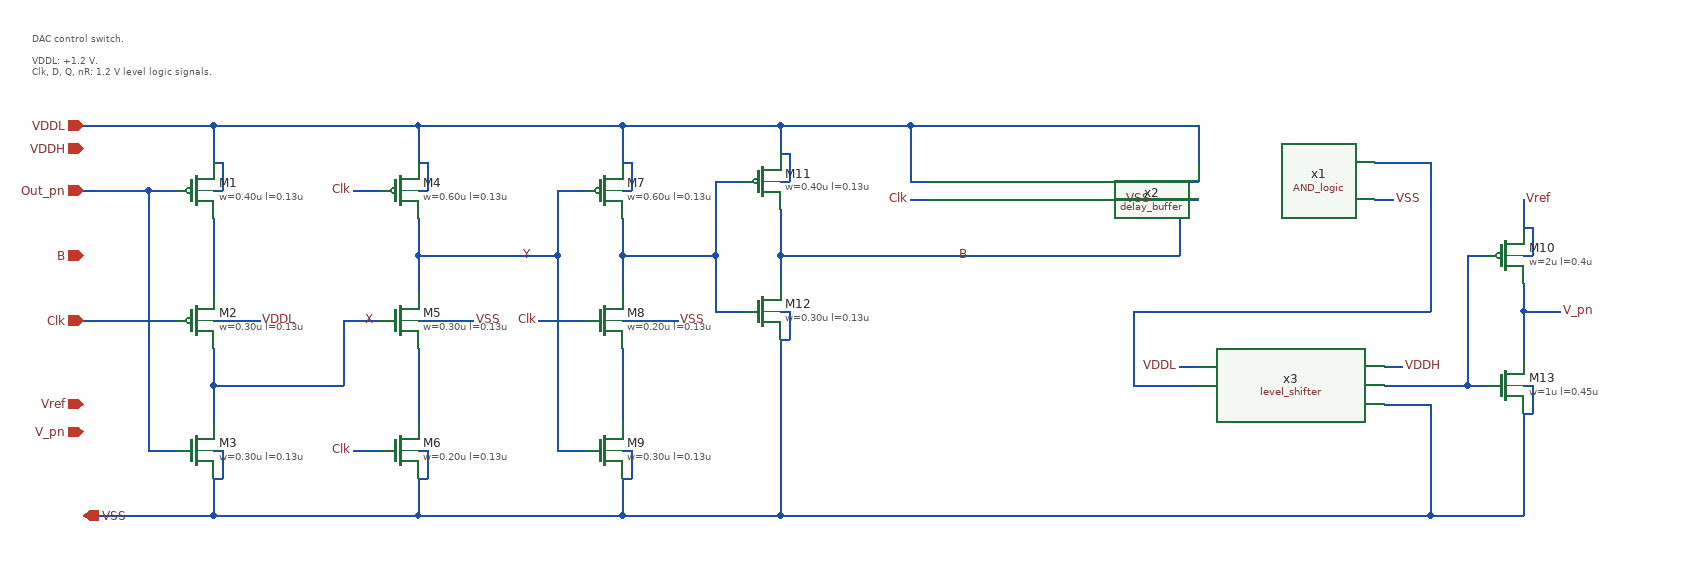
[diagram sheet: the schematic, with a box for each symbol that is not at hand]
v {xschem version=3.4.8RC file_version=1.3}
G {}
K {}
V {}
S {}
F {}
E {}
T {DAC control switch.

VDDL: +1.2 V.
Clk, D, Q, nR: 1.2 V level logic signals.} -245 -265 0 0 0.3 0.3 {}
N -50 -60 -50 20 {lab=#net1}
N -50 -160 -50 -120 {lab=VDDL}
N -50 120 -50 160 {lab=X}
N -50 220 -50 260 {lab=VSS}
N -50 -90 -40 -90 {lab=VDDL}
N -40 -120 -40 -90 {lab=VDDL}
N -50 -120 -40 -120 {lab=VDDL}
N -50 50 0 50 {lab=VDDL}
N -50 190 -40 190 {lab=VSS}
N -40 190 -40 220 {lab=VSS}
N -50 220 -40 220 {lab=VSS}
N -120 -90 -90 -90 {lab=Out_pn}
N -120 -90 -120 190 {lab=Out_pn}
N -120 190 -90 190 {lab=Out_pn}
N -190 -90 -120 -90 {lab=Out_pn}
N -190 50 -90 50 {lab=Clk}
N -190 -160 -50 -160 {lab=VDDL}
N -190 260 -50 260 {lab=VSS}
N 170 -90 180 -90 {lab=VDDL}
N 180 -120 180 -90 {lab=VDDL}
N 170 -120 180 -120 {lab=VDDL}
N 170 -160 170 -120 {lab=VDDL}
N -50 -160 170 -160 {lab=VDDL}
N 90 50 130 50 {lab=X}
N 90 50 90 120 {lab=X}
N -50 120 90 120 {lab=X}
N -50 80 -50 120 {lab=X}
N 100 -90 130 -90 {lab=Clk}
N 100 190 130 190 {lab=Clk}
N 170 80 170 160 {lab=#net2}
N 170 220 170 260 {lab=VSS}
N -50 260 170 260 {lab=VSS}
N 170 -20 170 20 {lab=Y}
N 170 50 230 50 {lab=VSS}
N 170 190 180 190 {lab=VSS}
N 180 190 180 220 {lab=VSS}
N 170 220 180 220 {lab=VSS}
N 390 -90 400 -90 {lab=VDDL}
N 400 -120 400 -90 {lab=VDDL}
N 390 -120 400 -120 {lab=VDDL}
N 390 -160 390 -120 {lab=VDDL}
N 390 80 390 160 {lab=#net3}
N 390 220 390 260 {lab=VSS}
N 390 -20 390 20 {lab=#net4}
N 390 50 450 50 {lab=VSS}
N 390 190 400 190 {lab=VSS}
N 400 190 400 220 {lab=VSS}
N 390 220 400 220 {lab=VSS}
N 320 -90 350 -90 {lab=Y}
N 320 -20 320 190 {lab=Y}
N 320 190 350 190 {lab=Y}
N 170 260 390 260 {lab=VSS}
N 170 -160 390 -160 {lab=VDDL}
N 170 -20 320 -20 {lab=Y}
N 170 -60 170 -20 {lab=Y}
N 320 -90 320 -20 {lab=Y}
N 390 -160 560 -160 {lab=VDDL}
N 300 50 350 50 {lab=Clk}
N 560 -100 570 -100 {lab=VDDL}
N 570 -130 570 -100 {lab=VDDL}
N 560 -130 570 -130 {lab=VDDL}
N 490 -100 520 -100 {lab=#net4}
N 560 -20 560 10 {lab=B}
N 560 40 570 40 {lab=VSS}
N 570 40 570 70 {lab=VSS}
N 560 70 570 70 {lab=VSS}
N 560 70 560 260 {lab=VSS}
N 390 260 560 260 {lab=VSS}
N 390 -60 390 -20 {lab=#net4}
N 490 -20 490 40 {lab=#net4}
N 490 -100 490 -20 {lab=#net4}
N 490 40 520 40 {lab=#net4}
N 390 -20 490 -20 {lab=#net4}
N 560 -160 560 -130 {lab=VDDL}
N 560 -70 560 -20 {lab=B}
N 910 -100 1010 -100 {lab=#net5}
N 910 -80 930 -80 {lab=VSS}
N 1200 -80 1220 -80 {lab=VSS}
N 1010 -160 1010 -120 {lab=VDDL}
N 700 -100 720 -100 {lab=VDDL}
N 700 -160 700 -100 {lab=VDDL}
N 700 -160 1010 -160 {lab=VDDL}
N 560 -160 700 -160 {lab=VDDL}
N 700 -80 720 -80 {lab=Clk}
N 560 -20 990 -20 {lab=B}
N 990 -80 990 -20 {lab=B}
N 990 -80 1010 -80 {lab=B}
N 1360 -20 1370 -20 {lab=Vref}
N 1370 -50 1370 -20 {lab=Vref}
N 1360 -50 1370 -50 {lab=Vref}
N 1300 -20 1320 -20 {lab=#net6}
N 1360 120 1370 120 {lab=VSS}
N 1370 120 1370 150 {lab=VSS}
N 1300 120 1320 120 {lab=#net6}
N 1360 40 1360 90 {lab=V_pn}
N 1360 -80 1360 -50 {lab=Vref}
N 1300 -20 1300 120 {lab=#net6}
N 1360 40 1400 40 {lab=V_pn}
N 1360 10 1360 40 {lab=V_pn}
N 1200 -120 1260 -120 {lab=#net7}
N 1260 -120 1260 40 {lab=#net7}
N 940 120 1010 120 {lab=#net7}
N 990 100 1010 100 {lab=VDDL}
N 940 40 1260 40 {lab=#net7}
N 940 40 940 120 {lab=#net7}
N 1360 150 1370 150 {lab=VSS}
N 1260 260 1360 260 {lab=VSS}
N 1360 150 1360 260 {lab=VSS}
N 1260 140 1260 260 {lab=VSS}
N 560 260 1260 260 {lab=VSS}
N 1210 100 1230 100 {lab=VDDH}
N 1210 120 1300 120 {lab=#net6}
N 1210 140 1260 140 {lab=VSS}
C {title.sym} -160 420 0 0 {name=l1 author="Ernestas Gruodis - Kaunas University of Technology"}
C {sg13g2_pr/sg13_lv_pmos.sym} -70 -90 0 0 {name=M1
l=0.13u
w=0.40u
ng=1
m=1
model=sg13_lv_pmos
spiceprefix=X
}
C {sg13g2_pr/sg13_lv_pmos.sym} -70 50 0 0 {name=M2
l=0.13u
w=0.30u
ng=1
m=1
model=sg13_lv_pmos
spiceprefix=X
}
C {sg13g2_pr/sg13_lv_nmos.sym} -70 190 0 0 {name=M3
l=0.13u
w=0.30u
ng=1
m=1
model=sg13_lv_nmos
spiceprefix=X
}
C {lab_wire.sym} 0 50 0 1 {name=p1 sig_type=std_logic lab=VDDL}
C {ipin.sym} -190 -90 0 0 {name=p2 lab=Out_pn}
C {ipin.sym} -190 50 0 0 {name=p3 lab=Clk}
C {ipin.sym} -190 -160 0 0 {name=p4 lab=VDDL}
C {sg13g2_pr/sg13_lv_pmos.sym} 150 -90 0 0 {name=M4
l=0.13u
w=0.60u
ng=1
m=1
model=sg13_lv_pmos
spiceprefix=X
}
C {sg13g2_pr/sg13_lv_nmos.sym} 150 50 0 0 {name=M5
l=0.13u
w=0.30u
ng=1
m=1
model=sg13_lv_nmos
spiceprefix=X
}
C {sg13g2_pr/sg13_lv_nmos.sym} 150 190 0 0 {name=M6
l=0.13u
w=0.20u
ng=1
m=1
model=sg13_lv_nmos
spiceprefix=X
}
C {lab_wire.sym} 110 50 0 1 {name=p6 sig_type=std_logic lab=X}
C {lab_wire.sym} 100 -90 0 0 {name=p7 sig_type=std_logic lab=Clk}
C {lab_wire.sym} 100 190 0 0 {name=p8 sig_type=std_logic lab=Clk}
C {lab_wire.sym} 230 50 0 1 {name=p9 sig_type=std_logic lab=VSS}
C {sg13g2_pr/sg13_lv_pmos.sym} 370 -90 0 0 {name=M7
l=0.13u
w=0.60u
ng=1
m=1
model=sg13_lv_pmos
spiceprefix=X
}
C {sg13g2_pr/sg13_lv_nmos.sym} 370 50 0 0 {name=M8
l=0.13u
w=0.20u
ng=1
m=1
model=sg13_lv_nmos
spiceprefix=X
}
C {sg13g2_pr/sg13_lv_nmos.sym} 370 190 0 0 {name=M9
l=0.13u
w=0.30u
ng=1
m=1
model=sg13_lv_nmos
spiceprefix=X
}
C {lab_wire.sym} 300 50 0 0 {name=p12 sig_type=std_logic lab=Clk}
C {lab_wire.sym} 450 50 0 1 {name=p13 sig_type=std_logic lab=VSS}
C {sg13g2_pr/sg13_lv_pmos.sym} 540 -100 0 0 {name=M11
l=0.13u
w=0.40u
ng=1
m=1
model=sg13_lv_pmos
spiceprefix=X
}
C {sg13g2_pr/sg13_lv_nmos.sym} 540 40 0 0 {name=M12
l=0.13u
w=0.30u
ng=1
m=1
model=sg13_lv_nmos
spiceprefix=X
}
C {lab_wire.sym} 280 -20 0 1 {name=p14 sig_type=std_logic lab=Y}
C {opin.sym} -190 -20 0 1 {name=p16 lab=B}
C {iopin.sym} -190 260 0 1 {name=p17 lab=VSS}
C {Projektai/SG13G2/SAR_ADC/AND_logic.sym} 1160 -100 0 0 {name=x1}
C {Projektai/SG13G2/SAR_ADC/delay_buffer.sym} 870 -90 0 0 {name=x2}
C {lab_wire.sym} 930 -80 2 0 {name=p5 sig_type=std_logic lab=VSS}
C {lab_wire.sym} 1220 -80 2 0 {name=p10 sig_type=std_logic lab=VSS}
C {lab_wire.sym} 700 -80 2 1 {name=p11 sig_type=std_logic lab=Clk}
C {lab_wire.sym} 750 -20 0 1 {name=p15 sig_type=std_logic lab=B}
C {lab_wire.sym} 1400 40 0 1 {name=p18 sig_type=std_logic lab=V_pn}
C {opin.sym} -190 170 0 1 {name=p19 lab=V_pn}
C {lab_wire.sym} 1360 -80 0 1 {name=p20 sig_type=std_logic lab=Vref}
C {ipin.sym} -190 140 0 0 {name=p21 lab=Vref}
C {Projektai/SG13G2/SAR_ADC/level_shifter.sym} 1010 100 0 0 {name=x3}
C {lab_wire.sym} 1230 100 0 1 {name=p23 sig_type=std_logic lab=VDDH}
C {lab_wire.sym} 990 100 0 0 {name=p24 sig_type=std_logic lab=VDDL}
C {ipin.sym} -190 -135 0 0 {name=p25 lab=VDDH}
C {sg13g2_pr/sg13_hv_pmos.sym} 1340 -20 0 0 {name=M10
l=0.4u
w=2u
ng=1
m=1
model=sg13_hv_pmos
spiceprefix=X
}
C {sg13g2_pr/sg13_hv_nmos.sym} 1340 120 0 0 {name=M13
l=0.45u
w=1u
ng=1
m=1
model=sg13_hv_nmos
spiceprefix=X
}
